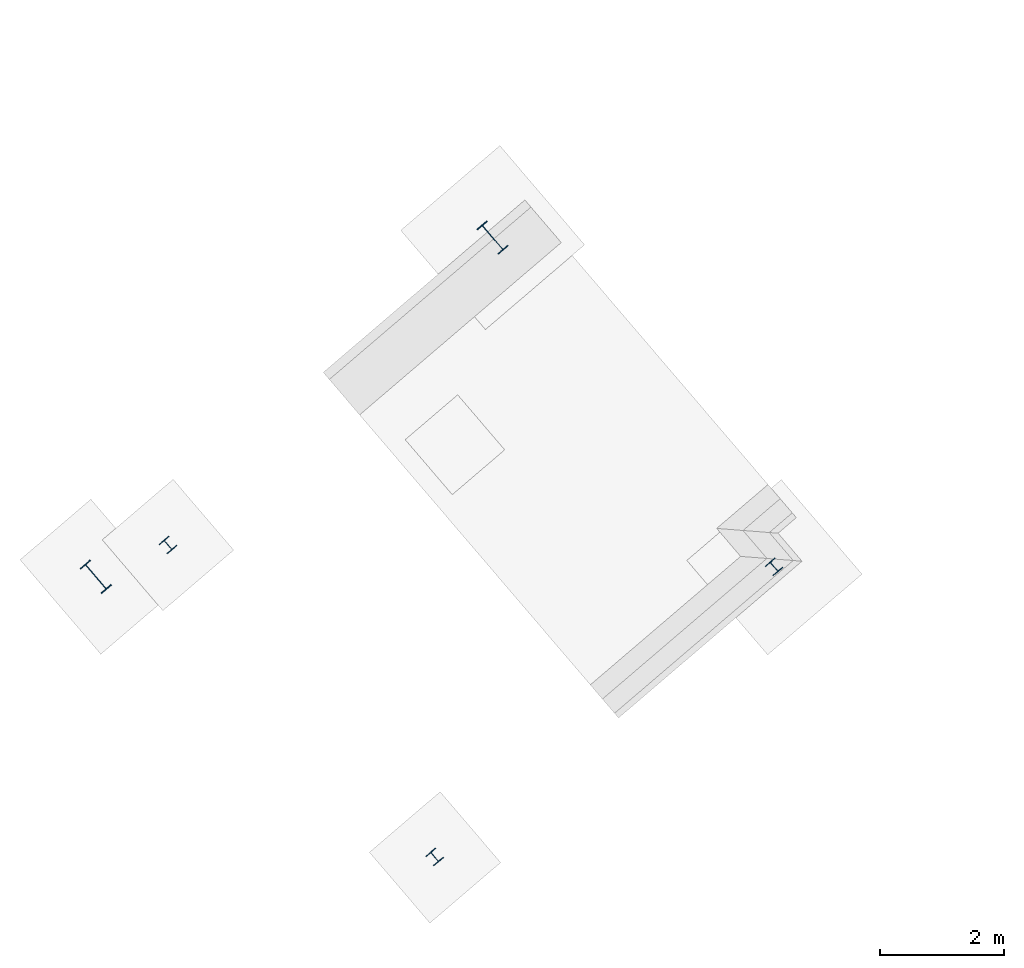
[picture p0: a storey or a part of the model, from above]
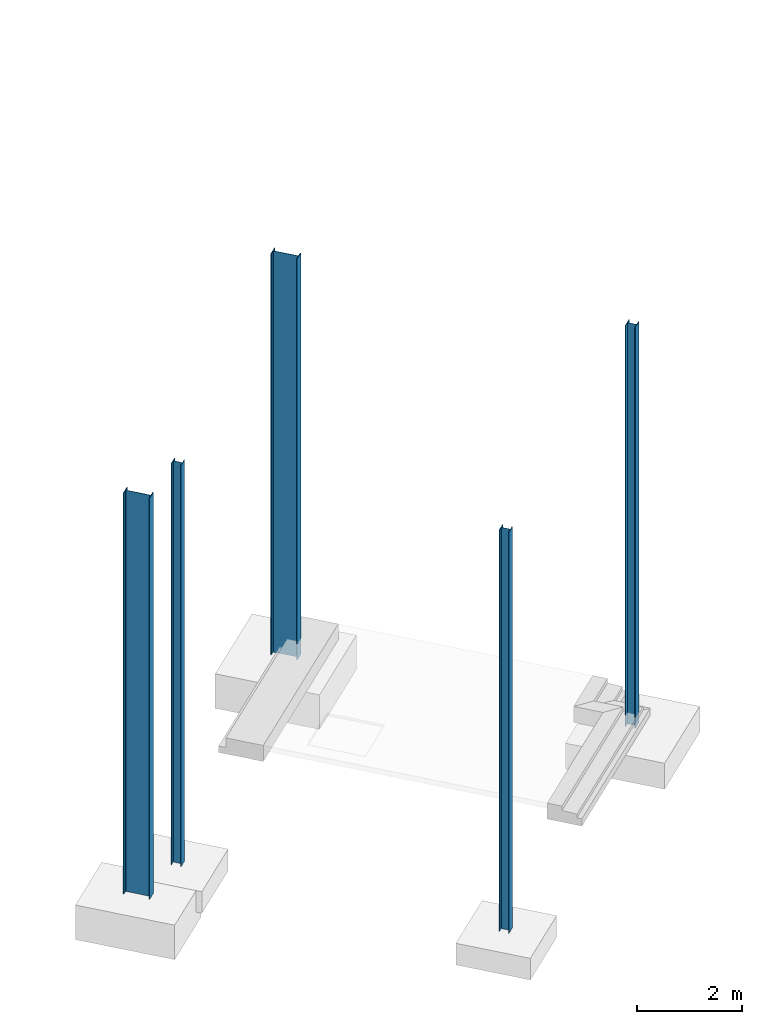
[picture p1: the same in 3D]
Properties of the parts of a building model (IFC2X3)

# File
Description: ViewDefinition [CoordinationView_V2.0]
File name: 12595320
Time: 2024-07-09T11:09:52
Organization: GHD
Written by: ODA IFC SDK 22.8
Made in: 22.1.30.34 - Exporter 22.1.30.34 - Alternate UI 22.1.30.34

# IfcProject, 12595320
LongName: REPOSITORY EXTENSION

# IfcSite, Default
RefLatitude: -33, -52, -58, -799999; RefLongitude: 151, 12, 57, 599999; RefElevation: 0 mm
Pset_ProductRequirements - Category: Project Information

# IfcBuilding
Pset_BuildingCommon - NumberOfStoreys: 4
Pset_ProductRequirements - Category: Project Information

# IfcBuildingStorey: Level:Name and Level (3)
Pset_ProductRequirements - Category: Levels
Name | LongName = Pset_AirSideSystemInformation, Name = Pset_ProductRequirements, Name | Elevation (mm)
Datum | Datum | 0
TOP OF PLANT ROOM | TOP OF PLANT ROOM | 8925
TOP OF CEILING | TOP OF CEILING | 9200

# IfcBeam: ADSK_AUS_Light Gauge-Joists:C20015 (52)
In: Datum
Type - Pset_BeamCommon - IsExternal: no; LoadBearing: yes
Type - Pset_ProductRequirements - Category: Structural Framing
Classification: B10 (Uniformat); Material: Metal - Light Gauge
Pset_BeamCommon - Slope: 0 deg; Reference: C20015
Pset_QuantityTakeOff - Reference: C20015; sets with these values: 2
Name (ADSK_AUS_Light Gauge-Joists:C20015:...) | Span (mm)
644386 | 7047
644389 | 7047
644392 | 7047
644395 | 7047
644398 | 7047
644401 | 7047
644404 | 7047
644407 | 7047
644410 | 7047
644413 | 7047
644416 | 7047
644419 | 7047
644422 | 7047
645018 | 6842
645021 | 6842
645024 | 6842
645027 | 6842
645030 | 6842
645033 | 6842
645036 | 6842
645039 | 6842
645042 | 6842
645045 | 6842
645048 | 6842
645051 | 6842
645054 | 6842
645382 | 4227
645385 | 7148
645388 | 7148
645391 | 7148
645394 | 7148
645397 | 7148
645400 | 7148
645403 | 7148
645406 | 7148
645409 | 7148
645412 | 7148
645415 | 7148
645418 | 7148
645987 | 6932
645990 | 6932
645993 | 6932
645996 | 6932
645999 | 6932
646002 | 6932
646005 | 6932
646008 | 6932
646011 | 6932
646014 | 6932
646017 | 6932
646020 | 6932
646023 | 6932

# IfcBeam: ADSK_AUS_Light Gauge-Joists:C20019 (18)
In: Datum
Type - Pset_BeamCommon - IsExternal: no; LoadBearing: yes
Type - Pset_ProductRequirements - Category: Structural Framing
Classification: B10 (Uniformat); Material: Metal - Light Gauge
Pset_BeamCommon - Slope: 0 deg; Reference: C20019
Pset_QuantityTakeOff - Reference: C20019; sets with these values: 2
Name (ADSK_AUS_Light Gauge-Joists:C20019:...) | Span (mm)
853535 | 5010
853538 | 5010
853541 | 5010
853544 | 5010
853547 | 5010
854987 | 2960
854990 | 2960
854993 | 2960
854996 | 2960
854999 | 2960
855749 | 3110
855751 | 3100
855753 | 580
855755 | 620
855757 | 610
856089 | 300
856175 | 325
856231 | 280

# IfcBeam: ADSK_AU_CHS-Circular Hollow Sections (AS 1163_C350):168.3x4.8CHS EXISTING, ADSK_AU_CHS-Circular Hollow Sections (AS 1163_C350):168.3x4.8CHS EXISTING:496924
In: TOP OF PLANT ROOM
Type - Pset_BeamCommon - IsExternal: no; LoadBearing: yes
Type - Pset_ProductRequirements - Category: Structural Framing
Material: <Unnamed>
Pset_BeamCommon - Slope: 0 deg; Reference: 168.3x4.8CHS EXISTING; Span: 29000 mm
Pset_QuantityTakeOff - Reference: 168.3x4.8CHS EXISTING; sets with these values: 2

# IfcBeam: ADSK_AU_CHS-Circular Hollow Sections (AS 1163_C350):168.3x6.4CHS (29)
Type - Pset_BeamCommon - IsExternal: no; LoadBearing: yes
Type - Pset_ProductRequirements - Category: Structural Framing
Type - Pset_ReinforcementBarPitchOfBeam - Description: STEEL FRAMING
Material: Metal - Steel - 300 MPa
Pset_BeamCommon - Reference: 168.3x6.4CHS
Pset_QuantityTakeOff - Reference: 168.3x6.4CHS
Pset_ReinforcementBarPitchOfBeam - Reference: 168.3x6.4CHS
Name (ADSK_AU_CHS-Circular Hollow Sections (AS 1163_C350):168.3x6.4CHS:...) | In | Span (mm) | Slope (deg)
447945 | TOP OF CEILING | 8400 | 0
448071 | TOP OF CEILING | 6360 | 0
450057 | TOP OF CEILING | 8400 | 0
450227 | TOP OF CEILING | 8400 | 0
450260 | TOP OF CEILING | 8400 | 0
451164 | TOP OF CEILING | 6420.5 | 0
452431 | TOP OF CEILING | 6360 | 0
453757 | TOP OF CEILING | 6760 | 0
456061 | TOP OF CEILING | 6480 | 0
456197 | TOP OF CEILING | 7460 | 0
456199 | TOP OF CEILING | 7467.4 | 0.000102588
456201 | TOP OF CEILING | 7460 | 0
457916 | TOP OF CEILING | 7767.7 | 0
458354 | TOP OF CEILING | 7760 | 0
461023 | TOP OF PLANT ROOM | 8100 | 0
466874 | TOP OF CEILING | 4400 | 0
486064 | TOP OF PLANT ROOM | 8400 | 0
505094 | TOP OF CEILING | 8400 | 0
505642 | TOP OF CEILING | 8400 | 0
506793 | TOP OF CEILING | 8400.1 | 0.287305
506808 | TOP OF CEILING | 8400 | 0
507253 | TOP OF CEILING | 6440 | 0
507673 | TOP OF CEILING | 7020 | 0
510809 | TOP OF PLANT ROOM | 6640 | 0
511162 | TOP OF PLANT ROOM | 6080 | 0
612038 | TOP OF PLANT ROOM | 6980 | 0
612040 | TOP OF PLANT ROOM | 7354.6 | 0
1066787 | TOP OF CEILING | 8275 | 0.000092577
1067047 | TOP OF CEILING | 8275 | 0.000092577

# IfcBeam: ADSK_AU_EA-Equal Angles (AS 3679_1):50x50x5EA (24)
In: TOP OF CEILING
Type - Pset_BeamCommon - IsExternal: no; LoadBearing: yes
Type - Pset_ProductRequirements - Category: Structural Framing
Type - Pset_ReinforcementBarPitchOfBeam - Description: STEEL FRAMING
Pset_BeamCommon - Reference: 50x50x5EA; Span: 660 mm; Slope: 37 deg
Pset_QuantityTakeOff - Reference: 50x50x5EA
Pset_ReinforcementBarPitchOfBeam - Reference: 50x50x5EA
Name (ADSK_AU_EA-Equal Angles (AS 3679_1):50x50x5EA:...)
516959
518426
518509
518511
518528
518530
518594
519063
519114
519116
519133
519135
519349
519351
519989
519991
520215
520217
520234
520236
520590
520592
520611
520613

# IfcBeam: ADSK_AU_EA-Equal Angles (AS 3679_1):65x65x6EA, ADSK_AU_EA-Equal Angles (AS 3679_1):65x65x6EA:1106605
In: Datum
Type - Pset_BeamCommon - IsExternal: no; LoadBearing: yes
Type - Pset_ProductRequirements - Category: Structural Framing
Type - Pset_ReinforcementBarPitchOfBeam - Description: STEEL FRAMING
Material: Metal - Steel - 300 MPa
Pset_BeamCommon - Slope: 0 deg; Reference: 65x65x6EA; Span: 270 mm
Pset_QuantityTakeOff - Reference: 65x65x6EA
Pset_ReinforcementBarPitchOfBeam - Reference: 65x65x6EA

# IfcBeam: ADSK_AU_EA-Equal Angles (AS 3679_1):90x90x10EA (26)
Type - Pset_BeamCommon - IsExternal: no; LoadBearing: yes
Type - Pset_ProductRequirements - Category: Structural Framing
Type - Pset_ReinforcementBarPitchOfBeam - Description: STEEL FRAMING
Material: Metal - Steel - 300 MPa
Pset_BeamCommon - Reference: 90x90x10EA
Pset_QuantityTakeOff - Reference: 90x90x10EA
Pset_ReinforcementBarPitchOfBeam - Reference: 90x90x10EA
Name (ADSK_AU_EA-Equal Angles (AS 3679_1):90x90x10EA:...) | In | Span (mm) | Slope (deg)
461464 | TOP OF PLANT ROOM | 10040.4 | 33.2153
461687 | TOP OF PLANT ROOM | 10040.4 | 33.2153
486003 | TOP OF PLANT ROOM | 10375 | 39.6164
486009 | TOP OF PLANT ROOM | 10100 | 36.7247
486487 | TOP OF PLANT ROOM | 10350 | 39.6335
486578 | TOP OF PLANT ROOM | 10060 | 36.708
507776 | TOP OF PLANT ROOM | 8880 | 38.3458
508056 | TOP OF PLANT ROOM | 8860 | 40.7268
508541 | TOP OF PLANT ROOM | 9480 | 42.2043
508543 | TOP OF PLANT ROOM | 9100 | 39.9247
611443 | TOP OF PLANT ROOM | 8460 | 38.695
611445 | TOP OF PLANT ROOM | 8860 | 41.9713
611447 | TOP OF PLANT ROOM | 9020 | 41.1549
611449 | TOP OF PLANT ROOM | 9420 | 43.3491
611451 | Datum | 8660 | 38.849
611453 | Datum | 8860 | 38.8348
611455 | Datum | 8900 | 38.0443
611457 | Datum | 8965 | 38.0468
671669 | Datum | 200 | 0
768591 | Datum | 8740 | 38.9314
768593 | Datum | 9020 | 39.7876
768827 | Datum | 8800 | 38.727
768829 | Datum | 8840 | 38.775
871857 | TOP OF PLANT ROOM | 10040.4 | 33.9341
871859 | TOP OF PLANT ROOM | 10040.5 | 33.2149
1080870 | Datum | 255 | 0

# IfcBeam: ADSK_AU_Light Gauge-Zeds:Z20012 (35)
Type - Pset_BeamCommon - IsExternal: no; LoadBearing: yes
Type - Pset_ProductRequirements - Category: Structural Framing
Classification: B10 (Uniformat); Material: Metal - Steel - 345 MPa
Pset_BeamCommon - Reference: Z20012
Pset_QuantityTakeOff - Reference: Z20012; sets with these values: 2
Name (ADSK_AU_Light Gauge-Zeds:Z20012:...) | In | Span (mm) | Slope (deg)
585773 | TOP OF CEILING | 29400 | 3.78054
585860 | TOP OF CEILING | 29400 | 3.78054
647515 | Datum | 8999 | 0
647518 | Datum | 8999 | 0
647521 | Datum | 8999 | 0
647524 | Datum | 8999 | 0
647527 | Datum | 8999 | 0
647530 | Datum | 8999 | 0
647533 | Datum | 8999 | 0
647536 | Datum | 8999 | 0
647539 | Datum | 8999 | 0
647542 | Datum | 8999 | 0
647545 | Datum | 8999 | 0
648481 | Datum | 8999 | 0
648483 | Datum | 8999 | 0
648485 | Datum | 8999 | 0
648487 | Datum | 8999 | 0
648489 | Datum | 8999 | 0
648491 | Datum | 8999 | 0
648493 | Datum | 8999 | 0
648495 | Datum | 8999 | 0
648497 | Datum | 8999 | 0
648499 | Datum | 8999 | 0
648501 | Datum | 8999 | 0
764615 | Datum | 8199 | 0
764617 | Datum | 8240 | 0
764619 | Datum | 8199 | 0
764621 | Datum | 8199 | 0
764623 | Datum | 8199 | 0
764625 | Datum | 8199 | 0
764627 | Datum | 8199 | 0
764629 | Datum | 8199 | 0
764631 | Datum | 8199 | 0
764633 | Datum | 8199 | 0
764635 | Datum | 8235 | 0

# IfcBeam: ADSK_AU_Light Gauge-Zeds:Z20015 (57)
Type - Pset_BeamCommon - IsExternal: no; LoadBearing: yes
Type - Pset_ProductRequirements - Category: Structural Framing
Classification: B10 (Uniformat)
Pset_BeamCommon - Slope: 0 deg; Reference: Z20015
Pset_QuantityTakeOff - Reference: Z20015; sets with these values: 2
Name (ADSK_AU_Light Gauge-Zeds:Z20015:...) | In | Material | Span (mm)
646382 | Datum | Metal - Steel - 345 MPa | 5284
646385 | Datum | Metal - Steel - 345 MPa | 5284
646388 | Datum | Metal - Steel - 345 MPa | 5284
649198 | Datum | Metal - Steel - 345 MPa | 7040
649200 | Datum | Metal - Steel - 345 MPa | 7040
649202 | Datum | Metal - Steel - 345 MPa | 7040
649204 | Datum | Metal - Steel - 345 MPa | 7040
649206 | Datum | Metal - Steel - 345 MPa | 7040
649208 | Datum | Metal - Steel - 345 MPa | 7040
649210 | Datum | Metal - Steel - 345 MPa | 7040
649212 | Datum | Metal - Steel - 345 MPa | 7040
649214 | Datum | Metal - Steel - 345 MPa | 7040
653207 | TOP OF CEILING | Metal - Steel - 345 MPa | 8164
653209 | TOP OF CEILING | Metal - Steel - 345 MPa | 8164
653211 | TOP OF CEILING | Metal - Steel - 345 MPa | 8164
653213 | TOP OF CEILING | Metal - Steel - 345 MPa | 8164
653215 | TOP OF CEILING | Metal - Steel - 345 MPa | 8164
653218 | TOP OF CEILING | Metal - Steel - 345 MPa | 8164
653220 | TOP OF CEILING | Metal - Steel - 345 MPa | 8164
653222 | TOP OF CEILING | Metal - Light Gauge | 8164
653224 | TOP OF CEILING | Metal - Steel - 345 MPa | 8164
653226 | TOP OF CEILING | Metal - Steel - 345 MPa | 8164
653228 | TOP OF CEILING | Metal - Steel - 345 MPa | 8164
653230 | TOP OF CEILING | Metal - Steel - 345 MPa | 8164
653232 | TOP OF CEILING | Metal - Steel - 345 MPa | 8164
653439 | TOP OF CEILING | Metal - Steel - 345 MPa | 8164
653441 | TOP OF CEILING | Metal - Steel - 345 MPa | 8164
653972 | TOP OF CEILING | Metal - Steel - 345 MPa | 9000
653974 | TOP OF CEILING | Metal - Steel - 345 MPa | 9000
653976 | TOP OF CEILING | Metal - Steel - 345 MPa | 9000
653978 | TOP OF CEILING | Metal - Steel - 345 MPa | 9000
653980 | TOP OF CEILING | Metal - Steel - 345 MPa | 9000
653983 | TOP OF CEILING | Metal - Steel - 345 MPa | 9000
653985 | TOP OF CEILING | Metal - Steel - 345 MPa | 9000
653987 | TOP OF CEILING | Metal - Steel - 345 MPa | 9000
653989 | TOP OF CEILING | Metal - Steel - 345 MPa | 9000
653991 | TOP OF CEILING | Metal - Steel - 345 MPa | 9000
653993 | TOP OF CEILING | Metal - Steel - 345 MPa | 9000
653995 | TOP OF CEILING | Metal - Steel - 345 MPa | 9000
653997 | TOP OF CEILING | Metal - Steel - 345 MPa | 9000
654001 | TOP OF CEILING | Metal - Steel - 345 MPa | 9000
654003 | TOP OF CEILING | Metal - Steel - 345 MPa | 9000
654415 | TOP OF CEILING | Metal - Steel - 345 MPa | 9000
654417 | TOP OF CEILING | Metal - Steel - 345 MPa | 9000
654419 | TOP OF CEILING | Metal - Steel - 345 MPa | 9000
654421 | TOP OF CEILING | Metal - Steel - 345 MPa | 9000
654423 | TOP OF CEILING | Metal - Steel - 345 MPa | 9000
654425 | TOP OF CEILING | Metal - Steel - 345 MPa | 9000
654427 | TOP OF CEILING | Metal - Steel - 345 MPa | 9000
654429 | TOP OF CEILING | Metal - Steel - 345 MPa | 9000
654431 | TOP OF CEILING | Metal - Steel - 345 MPa | 9000
654433 | TOP OF CEILING | Metal - Steel - 345 MPa | 9000
654435 | TOP OF CEILING | Metal - Steel - 345 MPa | 9000
654437 | TOP OF CEILING | Metal - Steel - 345 MPa | 9000
654439 | TOP OF CEILING | Metal - Steel - 345 MPa | 9000
654442 | TOP OF CEILING | Metal - Steel - 345 MPa | 9000
654444 | TOP OF CEILING | Metal - Steel - 345 MPa | 9000

# IfcBeam: ADSK_AU_Light Gauge-Zeds:Z20019 (15)
In: TOP OF CEILING
Type - Pset_BeamCommon - IsExternal: no; LoadBearing: yes
Type - Pset_ProductRequirements - Category: Structural Framing
Classification: B10 (Uniformat); Material: Metal - Light Gauge
Pset_BeamCommon - Slope: 0 deg; Reference: Z20019; Span: 7035 mm
Pset_QuantityTakeOff - Reference: Z20019; sets with these values: 2
Name (ADSK_AU_Light Gauge-Zeds:Z20019:...)
652011
652013
652015
652017
652019
652089
652091
652093
652095
652097
652099
652101
652103
652187
652189

# IfcBeam: ADSK_AU_Light Gauge-Zeds:Z20024 (40)
In: TOP OF CEILING
Type - Pset_BeamCommon - IsExternal: no; LoadBearing: yes
Type - Pset_ProductRequirements - Category: Structural Framing
Classification: B10 (Uniformat); Material: Metal - Light Gauge
Pset_BeamCommon - Slope: 0 deg; Reference: Z20024
Pset_QuantityTakeOff - Reference: Z20024; sets with these values: 2
Name (ADSK_AU_Light Gauge-Zeds:Z20024:...) | Span (mm)
646866 | 7035
646869 | 7035
646872 | 7035
646875 | 7035
646878 | 7035
652279 | 7035
652281 | 7035
652283 | 7035
652514 | 7035
652516 | 7035
652610 | 9000
652612 | 9000
652614 | 9000
652619 | 9000
652621 | 9000
652815 | 9000
652817 | 9000
652819 | 9000
652822 | 9000
652824 | 9000
653025 | 8192
653027 | 8192
653029 | 8192
653032 | 8192
653034 | 8192
653579 | 8161
653581 | 8161
653583 | 8161
653585 | 8161
653587 | 8161
653791 | 9000
653793 | 9000
653795 | 9000
653797 | 9000
653799 | 9000
654252 | 9000
654254 | 9000
654256 | 9000
654258 | 9000
654260 | 9000

# IfcBeam: ADSK_AU_PFC-Parallel Flange Channels (AS 3679_1):200PFC (8)
Type - Pset_BeamCommon - IsExternal: no; LoadBearing: yes
Type - Pset_ProductRequirements - Category: Structural Framing
Type - Pset_ReinforcementBarPitchOfBeam - Description: STEEL FRAMING
Material: Metal - Steel - 300 MPa
Pset_BeamCommon - Slope: 0 deg; Reference: 200PFC
Pset_QuantityTakeOff - Reference: 200PFC
Pset_ReinforcementBarPitchOfBeam - Reference: 200PFC
Name (ADSK_AU_PFC-Parallel Flange Channels (AS 3679_1):200PFC:...) | In | Span (mm)
476301 | TOP OF CEILING | 4560
494982 | TOP OF PLANT ROOM | 4240
495150 | TOP OF PLANT ROOM | 4240
495163 | TOP OF PLANT ROOM | 4240
495176 | TOP OF PLANT ROOM | 4240
495189 | TOP OF CEILING | 4240
495233 | TOP OF CEILING | 4240
495246 | TOP OF CEILING | 4240

# IfcBeam: ADSK_AU_PFC-Parallel Flange Channels (AS 3679_1):250PFC (3)
In: Datum
Type - Pset_BeamCommon - IsExternal: no; LoadBearing: yes
Type - Pset_ProductRequirements - Category: Structural Framing
Type - Pset_ReinforcementBarPitchOfBeam - Description: STEEL FRAMING
Material: Metal - Light Gauge Painted
Pset_BeamCommon - Reference: 250PFC
Pset_QuantityTakeOff - Reference: 250PFC
Pset_ReinforcementBarPitchOfBeam - Reference: 250PFC
Name (ADSK_AU_PFC-Parallel Flange Channels (AS 3679_1):250PFC:...) | Span (mm) | Slope (deg)
544530 | 3084 | 5.00001
545588 | 3222.7 | 5.00006
546929 | 5200 | 0

# IfcBeam: ADSK_AU_PFC-Parallel Flange Channels (AS 3679_1):300PFC, ADSK_AU_PFC-Parallel Flange Channels (AS 3679_1):300PFC:543160
In: Datum
Type - Pset_BeamCommon - IsExternal: no; LoadBearing: yes
Type - Pset_ProductRequirements - Category: Structural Framing
Type - Pset_ReinforcementBarPitchOfBeam - Description: STEEL FRAMING
Material: Metal - Light Gauge Painted
Pset_BeamCommon - Slope: 0 deg; Reference: 300PFC; Span: 7860 mm
Pset_QuantityTakeOff - Reference: 300PFC
Pset_ReinforcementBarPitchOfBeam - Reference: 300PFC

# IfcBeam: ADSK_AU_RHS-Rectangular Hollow Sections (AS 1163_C350):150x100x5.0RHS (3)
In: Datum
Type - Pset_BeamCommon - IsExternal: no; LoadBearing: yes
Type - Pset_ProductRequirements - Category: Structural Framing
Type - Pset_ReinforcementBarPitchOfBeam - Description: STEEL FRAMING
Pset_BeamCommon - Slope: 0 deg; Reference: 150x100x5.0RHS
Pset_QuantityTakeOff - Reference: 150x100x5.0RHS
Pset_ReinforcementBarPitchOfBeam - Reference: 150x100x5.0RHS
Name (ADSK_AU_RHS-Rectangular Hollow Sections (AS 1163_C350):150x100x5.0RHS:...) | Material | Span (mm)
540188 | Metal - Light Gauge Painted | 3060
570080 | Metal - Steel - 300 MPa | 6840
589344 | Metal - Steel - 300 MPa | 6745

# IfcBeam: ADSK_AU_Round Bars (AS 3679_1):20ROD (2)
In: Datum
Type - Pset_BeamCommon - IsExternal: no; LoadBearing: yes
Type - Pset_ProductRequirements - Category: Structural Framing
Type - Pset_ReinforcementBarPitchOfBeam - Description: STEEL FRAMING
Material: Metal - Light Gauge
Pset_BeamCommon - Reference: 20ROD
Pset_QuantityTakeOff - Reference: 20ROD
Pset_ReinforcementBarPitchOfBeam - Reference: 20ROD
Name (ADSK_AU_Round Bars (AS 3679_1):20ROD:...) | Span (mm) | Slope (deg)
547200 | 5820 | 2.46192
547300 | 5900 | 2.42851

# IfcBeam: ADSK_AU_Round Bars (AS 3679_1):24ROD (25)
In: TOP OF CEILING
Type - Pset_BeamCommon - IsExternal: no; LoadBearing: yes
Type - Pset_ProductRequirements - Category: Structural Framing
Pset_BeamCommon - Reference: 24ROD
Pset_QuantityTakeOff - Reference: 24ROD; sets with these values: 2
Name (ADSK_AU_Round Bars (AS 3679_1):24ROD:...) | Span (mm) | Slope (deg)
448184 | 9600 | 2.08937
448467 | 9732.1 | 4.3242
450519 | 9593.1 | 1.59011
450521 | 9600 | 3.28437
451956 | 9560 | 2.09812
451958 | 9660 | 2.96695
453718 | 9920 | 3.46759
453720 | 9700 | 2.65901
454938 | 10098.7 | 2.72434
454940 | 10280 | 2.78786
454942 | 10400 | 2.75567
454944 | 10380 | 3.31457
454946 | 10380 | 4.36488
454948 | 10210 | 2.91936
454950 | 10874.1 | 3.09905
454952 | 10860.2 | 1.10798
505726 | 11106.2 | 2.32214
505750 | 11100.3 | 1.3741
505855 | 10940 | 4.19356
505870 | 7251.6 | 0
505893 | 11099.2 | 1.11613
506960 | 11321.1 | 1.06287
507005 | 11321.1 | 1.06287 | Material: Colorbond Paint - Basalt
507054 | 11321.1 | 1.06287
507099 | 11321.1 | 1.06287

# IfcBeam: ADSK_AU_Round Bars (AS 3679_1):24ROD (EXISTING) (4)
Type - Pset_BeamCommon - IsExternal: no; LoadBearing: yes
Type - Pset_ProductRequirements - Category: Structural Framing
Pset_BeamCommon - Reference: 24ROD (EXISTING)
Pset_QuantityTakeOff - Reference: 24ROD (EXISTING); sets with these values: 2
Name (ADSK_AU_Round Bars (AS 3679_1):24ROD (EXISTING):...) | In | Span (mm) | Slope (deg)
497516 | TOP OF PLANT ROOM | 7400 | 39.3869
498346 | Datum | 7330 | 41.429
498640 | TOP OF PLANT ROOM | 9520 | 35.1426
498642 | Datum | 9080 | 32.1768

# IfcBeam: ADSK_AU_SHS-Square Hollow Sections (AS 1163_C350):150x150x6.0SHS (2)
In: Datum
Type - Pset_BeamCommon - IsExternal: no; LoadBearing: yes
Type - Pset_ProductRequirements - Category: Structural Framing
Type - Pset_ReinforcementBarPitchOfBeam - Description: STEEL FRAMING
Material: Metal - Steel - 300 MPa
Pset_BeamCommon - Slope: 0 deg; Reference: 150x150x6.0SHS
Pset_QuantityTakeOff - Reference: 150x150x6.0SHS
Pset_ReinforcementBarPitchOfBeam - Reference: 150x150x6.0SHS
Name (ADSK_AU_SHS-Square Hollow Sections (AS 1163_C350):150x150x6.0SHS:...) | Span (mm)
547857 | 7200
549237 | 7160

# IfcBeam: ADSK_AU_UB-Universal Beams (AS 3679_1):200UB18.2 (2)
In: TOP OF CEILING
Type - Pset_BeamCommon - IsExternal: no; LoadBearing: yes
Type - Pset_ProductRequirements - Category: Structural Framing
Type - Pset_ReinforcementBarPitchOfBeam - Description: STEEL FRAMING
Pset_BeamCommon - Reference: 200UB18.2
Pset_QuantityTakeOff - Reference: 200UB18.2
Pset_ReinforcementBarPitchOfBeam - Reference: 200UB18.2
Name (ADSK_AU_UB-Universal Beams (AS 3679_1):200UB18.2:...) | Span (mm) | Slope (deg)
469927 | 7163.5 | 84.3745
494460 | 6500 | 90

# IfcBeam: ADSK_AU_UB-Universal Beams (AS 3679_1):310UB40.4, ADSK_AU_UB-Universal Beams (AS 3679_1):310UB40.4:466103
In: TOP OF CEILING
Type - Pset_BeamCommon - IsExternal: no; LoadBearing: yes
Type - Pset_ProductRequirements - Category: Structural Framing
Type - Pset_ReinforcementBarPitchOfBeam - Description: STEEL FRAMING
Pset_BeamCommon - Reference: 310UB40.4; Span: 29660 mm; Slope: 3.98485 deg
Pset_QuantityTakeOff - Reference: 310UB40.4
Pset_ReinforcementBarPitchOfBeam - Reference: 310UB40.4

# IfcBeam: ADSK_UK_Light Gauge-Zeds-Purlin:Metsec-202Z14 (60)
Type - Pset_BeamCommon - IsExternal: no; LoadBearing: yes
Type - Pset_ProductRequirements - Category: Structural Framing
Classification: B10 (Uniformat); Material: Metal - Steel - 300 MPa
Pset_BeamCommon - Reference: Metsec-202Z14
Pset_QuantityTakeOff - Reference: Metsec-202Z14; sets with these values: 2
Name (ADSK_UK_Light Gauge-Zeds-Purlin:Metsec-202Z14:...) | In | Slope (deg) | Span (mm)
468644 | TOP OF PLANT ROOM | 0 | 4900
468943 | TOP OF PLANT ROOM | 0 | 4900
468957 | Datum | 0 | 4900
468971 | Datum | 0 | 4900
468985 | Datum | 0 | 4900
468999 | Datum | 0 | 4900
469013 | Datum | 0 | 4900
469087 | TOP OF PLANT ROOM | 0 | 29000
469690 | TOP OF PLANT ROOM | 0 | 29000
469703 | Datum | 0 | 29000
469718 | Datum | 0 | 24580
469733 | Datum | 0 | 2240
469748 | Datum | 0 | 2240
469763 | Datum | 0 | 2260
470765 | TOP OF CEILING | 0 | 6000
475768 | TOP OF CEILING | 0 | 1587
475872 | TOP OF CEILING | 0 | 6000
475885 | TOP OF CEILING | 0 | 5900
475899 | TOP OF CEILING | 0.00000625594 | 5951
475956 | TOP OF CEILING | 0 | 6000
476011 | TOP OF CEILING | 0 | 6000
476074 | TOP OF CEILING | 0 | 6000
476129 | TOP OF CEILING | 0 | 6000
476241 | TOP OF CEILING | 0 | 6000
476384 | TOP OF CEILING | 0 | 6000
493490 | TOP OF PLANT ROOM | 0 | 4240
494144 | TOP OF PLANT ROOM | 0 | 4240
494157 | TOP OF PLANT ROOM | 0 | 4240
494170 | TOP OF PLANT ROOM | 0 | 4240
494210 | TOP OF CEILING | 0 | 4240
494223 | TOP OF CEILING | 0 | 4240
494236 | TOP OF CEILING | 0 | 4240
494249 | TOP OF CEILING | 0 | 4240
494286 | TOP OF CEILING | 0 | 4240
496260 | TOP OF PLANT ROOM | 0.0182882 | 4640
496262 | TOP OF PLANT ROOM | 0.0454991 | 4640
496264 | Datum | 0 | 4680
496266 | Datum | 0 | 4900
496268 | Datum | 0 | 4900
496270 | Datum | 0 | 4660
496272 | Datum | 0 | 4680
499293 | TOP OF PLANT ROOM | 0 | 29000
499506 | TOP OF PLANT ROOM | 0 | 4660
499520 | TOP OF PLANT ROOM | 0 | 4680
499534 | TOP OF PLANT ROOM | 0 | 4520
499548 | TOP OF CEILING | 0 | 4695
500190 | TOP OF PLANT ROOM | 0 | 29000
500207 | TOP OF PLANT ROOM | 0 | 29000
500224 | TOP OF CEILING | 0 | 29000
500241 | TOP OF CEILING | 0 | 19300
500256 | TOP OF CEILING | 0 | 6920
501930 | TOP OF PLANT ROOM | 0 | 4900
502167 | TOP OF PLANT ROOM | 0 | 4900
513728 | Datum | 0 | 2220
513762 | Datum | 0 | 2220
513806 | Datum | 0 | 2220
666759 | Datum | 0 | 2220
668257 | Datum | 0 | 20200
668333 | Datum | 0 | 20160
668767 | Datum | 0 | 20160

# IfcBuildingElementProxy: Fascia Purlin:Fascia Purlin, Fascia Purlin:Fascia Purlin:1133160
In: TOP OF CEILING
Type - Material: <Unnamed>
Type - Pset_ProductRequirements - Category: Structural Framing
Pset_BuildingElementProxyCommon - Reference: Fascia Purlin; sets with these values: 2
Pset_ProvisionForVoid - Depth: 31400 mm

# IfcBuildingElementProxy: Slab Edge:Thickening Edge (3)
In: Datum
Type - Pset_ProductRequirements - Category: Floors: Slab Edges
Pset_BuildingElementProxyCommon - Reference: Thickening Edge; sets with these values: 2
Name (Slab Edge:Thickening Edge:...)
1080158
1083220
1083226

# IfcBuildingElementProxy: Slab Edge:Thickening Edge 2, Slab Edge:Thickening Edge 2:1086235
In: Datum
Type - Pset_ProductRequirements - Category: Floors: Slab Edges
Pset_BuildingElementProxyCommon - Reference: Thickening Edge 2; sets with these values: 2
Pset_ProvisionForVoid - Shape: Undefined; Depth: 4268.39 mm

# IfcColumn: ADSK_AU_SHS-Square Hollow Sections-Column (AS 1163_C350):100x100x5.0SHS (8)
In: Datum
Type - PredefinedType: COLUMN; Material: Metal - Steel - 300 MPa
Type - Pset_ColumnCommon - IsExternal: no; LoadBearing: yes
Type - Pset_ProductRequirements - Category: Structural Columns
Type - Pset_ReinforcementBarPitchOfColumn - Description: STEEL COLUMN
Pset_ColumnCommon - Reference: 100x100x5.0SHS
Pset_QuantityTakeOff - Reference: 100x100x5.0SHS
Pset_ReinforcementBarPitchOfColumn - Reference: 100x100x5.0SHS
Name (ADSK_AU_SHS-Square Hollow Sections-Column (AS 1163_C350):100x100x5.0SHS:...)
538913
539372
548377
549239
569776
589556
666456
667581

# IfcColumn: ADSK_AU_SHS-Square Hollow Sections-Column (AS 1163_C350):150x150x5.0SHS (3)
In: Datum
Type - PredefinedType: COLUMN; Material: Metal - Steel - 300 MPa
Type - Pset_ColumnCommon - IsExternal: no; LoadBearing: yes
Type - Pset_ProductRequirements - Category: Structural Columns
Type - Pset_ReinforcementBarPitchOfColumn - Description: STEEL COLUMN
Pset_ColumnCommon - Reference: 150x150x5.0SHS
Pset_QuantityTakeOff - Reference: 150x150x5.0SHS
Pset_ReinforcementBarPitchOfColumn - Reference: 150x150x5.0SHS
Name (ADSK_AU_SHS-Square Hollow Sections-Column (AS 1163_C350):150x150x5.0SHS:...)
539430
539738
539761

# IfcColumn: ADSK_AU_UB-Universal Beams-Column (AS 3679_1):360UB44.7 (EXISTING) (3)
In: Datum
Type - PredefinedType: COLUMN; Material: Metal - Steel - 300 MPa
Type - Pset_ColumnCommon - IsExternal: no; LoadBearing: yes
Type - Pset_ProductRequirements - Category: Structural Columns
Pset_ColumnCommon - Reference: 360UB44.7 (EXISTING)
Pset_QuantityTakeOff - Reference: 360UB44.7 (EXISTING); sets with these values: 2
Name (ADSK_AU_UB-Universal Beams-Column (AS 3679_1):360UB44.7 (EXISTING):...)
445959
445974
445991

# IfcColumn: ADSK_AU_UB-Universal Beams-Column (AS 3679_1):460UB67.1 (2)
In: Datum
Type - PredefinedType: COLUMN; Material: Metal - Steel - 300 MPa
Type - Pset_ColumnCommon - IsExternal: no; LoadBearing: yes
Type - Pset_ProductRequirements - Category: Structural Columns
Type - Pset_ReinforcementBarPitchOfColumn - Description: STEEL COLUMN
Description: BP{9986EAF8-8209-4BFB-B9E4-6B7E1651E2E1}
Pset_ColumnCommon - Reference: 460UB67.1
Pset_QuantityTakeOff - Reference: 460UB67.1
Pset_ReinforcementBarPitchOfColumn - Reference: 460UB67.1
ProfileProperties - SectionFamily: {3C230476-3704-4959-9E77-0935CE245F3A}BP; Section: BP{9986EAF8-8209-4BFB-B9E4-6B7E1651E2E1}
Name (ADSK_AU_UB-Universal Beams-Column (AS 3679_1):460UB67.1:...)
622792
610739

# IfcColumn: ADSK_AU_UB-Universal Beams-Column (AS 3679_1):530UB92.4 (15)
In: Datum
Type - PredefinedType: COLUMN; Material: Metal - Steel - 300 MPa
Type - Pset_ColumnCommon - IsExternal: no; LoadBearing: yes
Type - Pset_ProductRequirements - Category: Structural Columns
Type - Pset_ReinforcementBarPitchOfColumn - Description: STEEL COLUMN
Pset_ColumnCommon - Reference: 530UB92.4
Pset_QuantityTakeOff - Reference: 530UB92.4
Pset_ReinforcementBarPitchOfColumn - Reference: 530UB92.4
Name (ADSK_AU_UB-Universal Beams-Column (AS 3679_1):530UB92.4:...) | Description = Section | SectionFamily
445778
445924
447251
447313
447328
1073207
1073524
623076 | BP{3C230476-3704-4959-9E77-0935CE245F3A} | {3C230476-3704-4959-9E77-0935CE245F3A}BP
622994 | BP{3C230476-3704-4959-9E77-0935CE245F3A} | {3C230476-3704-4959-9E77-0935CE245F3A}BP
622851 | BP{3C230476-3704-4959-9E77-0935CE245F3A} | {3C230476-3704-4959-9E77-0935CE245F3A}BP
449362 | BP{3C230476-3704-4959-9E77-0935CE245F3A} | {3C230476-3704-4959-9E77-0935CE245F3A}BP
446577 | BP{3C230476-3704-4959-9E77-0935CE245F3A} | {3C230476-3704-4959-9E77-0935CE245F3A}BP
446625 | BP{3C230476-3704-4959-9E77-0935CE245F3A} | {3C230476-3704-4959-9E77-0935CE245F3A}BP
446642 | BP{3C230476-3704-4959-9E77-0935CE245F3A} | {3C230476-3704-4959-9E77-0935CE245F3A}BP
623118 | BP{3C230476-3704-4959-9E77-0935CE245F3A} | {3C230476-3704-4959-9E77-0935CE245F3A}BP

# IfcColumn: ADSK_AU_UC-Universal Columns-Column (AS 3679_1):200UC46.2 (3)
In: Datum
Type - PredefinedType: COLUMN; Material: Metal - Steel - 300 MPa
Type - Pset_ColumnCommon - IsExternal: no; LoadBearing: yes
Type - Pset_ProductRequirements - Category: Structural Columns
Type - Pset_ReinforcementBarPitchOfColumn - Description: STEEL COLUMN
Pset_ColumnCommon - Reference: 200UC46.2
Pset_QuantityTakeOff - Reference: 200UC46.2
Pset_ReinforcementBarPitchOfColumn - Reference: 200UC46.2
Name (ADSK_AU_UC-Universal Columns-Column (AS 3679_1):200UC46.2:...)
1073393
1073455
1073601

# IfcColumn: ADSK_AU_UC-Universal Columns-Column (AS 3679_1):310UC118 (5)
In: Datum
Type - PredefinedType: COLUMN; Material: Metal - Steel - 300 MPa
Type - Pset_ColumnCommon - IsExternal: no; LoadBearing: yes
Type - Pset_ProductRequirements - Category: Structural Columns
Type - Pset_ReinforcementBarPitchOfColumn - Description: STEEL COLUMN
Pset_ColumnCommon - Reference: 310UC118
Pset_QuantityTakeOff - Reference: 310UC118
Pset_ReinforcementBarPitchOfColumn - Reference: 310UC118
Name (ADSK_AU_UC-Universal Columns-Column (AS 3679_1):310UC118:...)
444763
444779
610593
610597
615597

# IfcColumn: ADSK_AU_UC-Universal Columns-Column (AS 3679_1):310UC118, ADSK_AU_UC-Universal Columns-Column (AS 3679_1):310UC118:444334
In: Datum
Type - PredefinedType: COLUMN; Material: Metal - Steel - ASTM A36
Type - Pset_ColumnCommon - IsExternal: no; LoadBearing: yes
Type - Pset_ProductRequirements - Category: Structural Columns
Type - Pset_ReinforcementBarPitchOfColumn - Description: STEEL COLUMN
Pset_ColumnCommon - Reference: 310UC118
Pset_QuantityTakeOff - Reference: 310UC118
Pset_ReinforcementBarPitchOfColumn - Reference: 310UC118

# IfcElementAssembly: Structural Beam System:Structural Beam System 1 (21)
PredefinedType: BEAM_GRID
Pset_ProductRequirements - Category: Structural Beam Systems
Pset_QuantityTakeOff - Reference: Structural Beam System 1
Name (Structural Beam System:Structural Beam System 1:...) | In
644317 | Datum
644973 | Datum
645354 | Datum
645959 | Datum
646284 | Datum
646809 | TOP OF CEILING
647410 | Datum
648475 | Datum
652005 | TOP OF CEILING
652274 | TOP OF CEILING
652605 | TOP OF CEILING
652810 | TOP OF CEILING
653020 | TOP OF CEILING
653202 | TOP OF CEILING
653573 | TOP OF CEILING
653785 | TOP OF CEILING
653967 | TOP OF CEILING
654246 | TOP OF CEILING
654410 | TOP OF CEILING
853458 | Datum
854653 | Datum

# IfcMember: ADSK_AU_Light Gauge-Zeds:Z20012 (22)
Type - PredefinedType: BRACE; Classification: B10 (Uniformat); Material: Metal - Steel - 345 MPa
Type - Pset_MemberCommon - IsExternal: no; LoadBearing: yes
Type - Pset_ProductRequirements - Category: Structural Framing
Pset_MemberCommon - Slope: 0 deg; Reference: Z20012
Pset_QuantityTakeOff - Reference: Z20012
Name (ADSK_AU_Light Gauge-Zeds:Z20012:...) | In | Span (mm)
568773 | TOP OF PLANT ROOM | 9240
568775 | TOP OF PLANT ROOM | 9240
568777 | TOP OF PLANT ROOM | 9240
568779 | TOP OF CEILING | 8700
568781 | TOP OF CEILING | 8500
568852 | Datum | 9240
568893 | Datum | 9240
568907 | Datum | 9240
568921 | Datum | 9240
980656 | Datum | 11100
980658 | Datum | 11100
980660 | Datum | 11100
980662 | Datum | 11200
980668 | TOP OF PLANT ROOM | 9240
980670 | TOP OF CEILING | 9240
980672 | TOP OF CEILING | 9240
980861 | TOP OF PLANT ROOM | 9240
980863 | TOP OF PLANT ROOM | 9240
980865 | TOP OF CEILING | 8700
980867 | TOP OF CEILING | 8500
981292 | TOP OF PLANT ROOM | 9240
981898 | TOP OF PLANT ROOM | 8400

# IfcMember: ADSK_AU_Light Gauge-Zeds:Z20015 (11)
Type - PredefinedType: BRACE; Classification: B10 (Uniformat); Material: Metal - Steel - 345 MPa
Type - Pset_MemberCommon - IsExternal: no; LoadBearing: yes
Type - Pset_ProductRequirements - Category: Structural Framing
Pset_MemberCommon - Slope: 0 deg; Reference: Z20015
Pset_QuantityTakeOff - Reference: Z20015
Name (ADSK_AU_Light Gauge-Zeds:Z20015:...) | In | Span (mm)
564058 | Datum | 5645
564060 | Datum | 7360
980483 | Datum | 7500
980485 | Datum | 11100
980487 | Datum | 11100
980489 | Datum | 11100
980491 | TOP OF PLANT ROOM | 9240
980493 | TOP OF PLANT ROOM | 9240
980495 | TOP OF PLANT ROOM | 9240
980497 | TOP OF CEILING | 7300
980499 | TOP OF CEILING | 7600

# IfcMember: ADSK_AU_Round Bars (AS 3679_1):20ROD (4)
In: Datum
Type - PredefinedType: BRACE; Material: <Unnamed>
Type - Pset_MemberCommon - IsExternal: no; LoadBearing: yes
Type - Pset_ProductRequirements - Category: Structural Framing
Pset_MemberCommon - Reference: 20ROD
Pset_QuantityTakeOff - Reference: 20ROD
Name (ADSK_AU_Round Bars (AS 3679_1):20ROD:...) | Span (mm) | Slope (deg)
540915 | 5760 | 59.9919
837828 | 6680 | 45
852895 | 6680 | 45
939976 | 5902.1 | 58.7219

# IfcMember: ADSK_AU_UB-Universal Beams (AS 3679_1):410UB53.7, ADSK_AU_UB-Universal Beams (AS 3679_1):410UB53.7:611441
In: TOP OF CEILING
Type - PredefinedType: MEMBER; Material: Metal - Steel - 300 MPa
Type - Pset_MemberCommon - IsExternal: no; LoadBearing: yes
Type - Pset_ProductRequirements - Category: Structural Framing
Description: BP{65F570B7-3AC5-4045-A480-5CB0B2FCD890}
Pset_MemberCommon - Reference: 410UB53.7; Span: 29480.5 mm; Slope: 3.99999 deg
Pset_QuantityTakeOff - Reference: 410UB53.7
ProfileProperties - SectionFamily: {3C230476-3704-4959-9E77-0935CE245F3A}BP; Section: BP{65F570B7-3AC5-4045-A480-5CB0B2FCD890}

# IfcMember: ADSK_AU_UB-Universal Beams (AS 3679_1):460UB67.1, ADSK_AU_UB-Universal Beams (AS 3679_1):460UB67.1:454585
In: TOP OF CEILING
Type - PredefinedType: MEMBER; Material: Metal - Steel - 300 MPa
Type - Pset_MemberCommon - IsExternal: no; LoadBearing: yes
Type - Pset_ProductRequirements - Category: Structural Framing
Description: BP{9986EAF8-8209-4BFB-B9E4-6B7E1651E2E1}
Pset_MemberCommon - Reference: 460UB67.1; Span: 28728.9 mm; Slope: 4.00001 deg
Pset_QuantityTakeOff - Reference: 460UB67.1
ProfileProperties - SectionFamily: {3C230476-3704-4959-9E77-0935CE245F3A}BP; Section: BP{9986EAF8-8209-4BFB-B9E4-6B7E1651E2E1}

# IfcMember: ADSK_AU_UB-Universal Beams (AS 3679_1):530UB92.4 (3)
In: TOP OF CEILING
Type - PredefinedType: MEMBER; Material: Metal - Steel - 300 MPa
Type - Pset_MemberCommon - IsExternal: no; LoadBearing: yes
Type - Pset_ProductRequirements - Category: Structural Framing
Description: BP{3C230476-3704-4959-9E77-0935CE245F3A}
Pset_MemberCommon - Reference: 530UB92.4
Pset_QuantityTakeOff - Reference: 530UB92.4
ProfileProperties - SectionFamily: {3C230476-3704-4959-9E77-0935CE245F3A}BP; Section: BP{3C230476-3704-4959-9E77-0935CE245F3A}
Name (ADSK_AU_UB-Universal Beams (AS 3679_1):530UB92.4:...) | Span (mm) | Slope (deg)
447866 | 29307.5 | 3.99999
447601 | 29308.3 | 4
447848 | 29307.5 | 3.99999

# IfcOpeningElement: Opening (11)
Name | In
4 x Basic Wall:Cast In Situ - Concrete 200 RW2:426313 | Datum | Pset_ElementShading - Roughness: 304.8 mm; Pset_ManufacturerTypeInformation - Manufacturer: BW; Pset_OpeningElementCommon - Reference: Cast In Situ - Concrete 200 RW2; sets with these values: 2; Pset_ProductRequirements - Category: Lines: <Sketch>
Floor:FL-GHD-Cast In Situ - Concrete 120:1073663:2 | Datum | Pset_ElementShading - Roughness: 304.8 mm; Pset_OpeningElementCommon - Reference: FL-GHD-Cast In Situ - Concrete 120; sets with these values: 2; Pset_ProductRequirements - Category: Floors
6 x  | TOP OF CEILING

# IfcPlate (12)
Description: -; Material: Metal-Steel-Galvanised
Pset_PlateCommon - Reference: Not defined; IsExternal: no; LoadBearing: no
Name | In
10 x - | TOP OF CEILING
2 x - | Datum

# IfcSlab: FT-GHD-Pad:1500x1500x500 (2)
In: Datum
Type - PredefinedType: BASESLAB; Material: GHD-Concrete-Concrete_InSitu
Type - Pset_ManufacturerTypeInformation - Manufacturer: GHD
Type - Pset_ProductRequirements - Category: Structural Foundations
Type - Pset_ReinforcementBarPitchOfSlab - Description: PAD FOOTING
Type - Pset_SlabCommon - IsExternal: no
Classification: Pr_20_85_13_32 (Uniformat)
Pset_QuantityTakeOff - Reference: 1500x1500x500
Pset_ReinforcementBarPitchOfSlab - Reference: 1500x1500x500
Pset_SlabCommon - PitchAngle: 0 deg; Reference: 1500x1500x500
Name (FT-GHD-Pad:1500x1500x500:...)
1072004
1072356

# IfcSlab: FT-GHD-Pad:1500x2000x800 (2)
In: Datum
Type - PredefinedType: BASESLAB; Material: GHD-Concrete-Concrete_InSitu
Type - Pset_ManufacturerTypeInformation - Manufacturer: GHD
Type - Pset_ProductRequirements - Category: Structural Foundations
Type - Pset_ReinforcementBarPitchOfSlab - Description: PAD FOOTING
Type - Pset_SlabCommon - IsExternal: no
Classification: Pr_20_85_13_32 (Uniformat)
Pset_QuantityTakeOff - Reference: 1500x2000x800
Pset_ReinforcementBarPitchOfSlab - Reference: 1500x2000x800
Pset_SlabCommon - Reference: 1500x2000x800
Name (FT-GHD-Pad:1500x2000x800:...)
445333
445382 | Pset_SlabCommon - PitchAngle: 0 deg

# IfcSlab: FT-GHD-Pad:1500x800x950 2 (2)
In: Datum
Type - PredefinedType: BASESLAB; Material: GHD-Concrete-Concrete_InSitu
Type - Pset_ManufacturerTypeInformation - Manufacturer: GHD
Type - Pset_ProductRequirements - Category: Structural Foundations
Type - Pset_ReinforcementBarPitchOfSlab - Description: PAD FOOTING
Type - Pset_SlabCommon - IsExternal: no
Classification: Pr_20_85_13_32 (Uniformat)
Pset_QuantityTakeOff - Reference: 1500x800x950 2
Pset_ReinforcementBarPitchOfSlab - Reference: 1500x800x950 2
Pset_SlabCommon - PitchAngle: 0 deg; Reference: 1500x800x950 2
Name (FT-GHD-Pad:1500x800x950 2:...)
600472
604338

# IfcSlab: FT-GHD-Pad:1550x1800x1800 (4)
In: Datum
Type - PredefinedType: BASESLAB; Material: GHD-Concrete-Concrete_InSitu
Type - Pset_ManufacturerTypeInformation - Manufacturer: GHD
Type - Pset_ProductRequirements - Category: Structural Foundations
Type - Pset_ReinforcementBarPitchOfSlab - Description: PAD FOOTING
Type - Pset_SlabCommon - IsExternal: no
Classification: Pr_20_85_13_32 (Uniformat)
Pset_QuantityTakeOff - Reference: 1550x1800x1800
Pset_ReinforcementBarPitchOfSlab - Reference: 1550x1800x1800
Pset_SlabCommon - Reference: 1550x1800x1800
Name (FT-GHD-Pad:1550x1800x1800:...)
601594
605394
605727
605736

# IfcSlab: FT-GHD-Pad:1700x1000x1000 (2)
In: Datum
Type - PredefinedType: BASESLAB; Material: GHD-Concrete-Concrete_InSitu
Type - Pset_ManufacturerTypeInformation - Manufacturer: GHD
Type - Pset_ProductRequirements - Category: Structural Foundations
Type - Pset_ReinforcementBarPitchOfSlab - Description: PAD FOOTING
Type - Pset_SlabCommon - IsExternal: no
Classification: Pr_20_85_13_32 (Uniformat)
Pset_QuantityTakeOff - Reference: 1700x1000x1000
Pset_ReinforcementBarPitchOfSlab - Reference: 1700x1000x1000
Pset_SlabCommon - Reference: 1700x1000x1000
Name (FT-GHD-Pad:1700x1000x1000:...)
599181
605802

# IfcSlab: FT-GHD-Pad:1700x1700x800 (3)
In: Datum
Type - PredefinedType: BASESLAB; Material: GHD-Concrete-Concrete_InSitu
Type - Pset_ManufacturerTypeInformation - Manufacturer: GHD
Type - Pset_ProductRequirements - Category: Structural Foundations
Type - Pset_ReinforcementBarPitchOfSlab - Description: PAD FOOTING
Type - Pset_SlabCommon - IsExternal: no
Classification: Pr_20_85_13_32 (Uniformat)
Pset_QuantityTakeOff - Reference: 1700x1700x800
Pset_ReinforcementBarPitchOfSlab - Reference: 1700x1700x800
Pset_SlabCommon - Reference: 1700x1700x800
Name (FT-GHD-Pad:1700x1700x800:...)
445431
445676
445685

# IfcSlab: FT-GHD-Pad:1800x1800x800 (3)
In: Datum
Type - PredefinedType: BASESLAB; Material: GHD-Concrete-Concrete_InSitu
Type - Pset_ManufacturerTypeInformation - Manufacturer: GHD
Type - Pset_ProductRequirements - Category: Structural Foundations
Type - Pset_ReinforcementBarPitchOfSlab - Description: PAD FOOTING
Type - Pset_SlabCommon - IsExternal: no
Classification: Pr_20_85_13_32 (Uniformat)
Pset_QuantityTakeOff - Reference: 1800x1800x800
Pset_ReinforcementBarPitchOfSlab - Reference: 1800x1800x800
Pset_SlabCommon - PitchAngle: 0 deg; Reference: 1800x1800x800
Name (FT-GHD-Pad:1800x1800x800:...)
598261
598632
598755

# IfcSlab: FT-GHD-Pad:2000x1500x800, FT-GHD-Pad:2000x1500x800:1072738
In: Datum
Type - PredefinedType: BASESLAB; Material: GHD-Concrete-Concrete_InSitu
Type - Pset_ManufacturerTypeInformation - Manufacturer: GHD
Type - Pset_ProductRequirements - Category: Structural Foundations
Type - Pset_ReinforcementBarPitchOfSlab - Description: PAD FOOTING
Type - Pset_SlabCommon - IsExternal: no
Classification: Pr_20_85_13_32 (Uniformat)
Pset_QuantityTakeOff - Reference: 2000x1500x800
Pset_ReinforcementBarPitchOfSlab - Reference: 2000x1500x800
Pset_SlabCommon - Reference: 2000x1500x800

# IfcSlab: FT-GHD-Pad:2000x2000x600, FT-GHD-Pad:2000x2000x600:1071500
In: Datum
Type - PredefinedType: BASESLAB; Material: GHD-Concrete-Concrete_InSitu
Type - Pset_ManufacturerTypeInformation - Manufacturer: GHD
Type - Pset_ProductRequirements - Category: Structural Foundations
Type - Pset_ReinforcementBarPitchOfSlab - Description: PAD FOOTING
Type - Pset_SlabCommon - IsExternal: no
Classification: Pr_20_85_13_32 (Uniformat)
Pset_QuantityTakeOff - Reference: 2000x2000x600
Pset_ReinforcementBarPitchOfSlab - Reference: 2000x2000x600
Pset_SlabCommon - Reference: 2000x2000x600

# IfcSlab: FT-GHD-Pad:2000x3500x1000 (2)
In: Datum
Type - PredefinedType: BASESLAB; Material: GHD-Concrete-Concrete_InSitu
Type - Pset_ManufacturerTypeInformation - Manufacturer: GHD
Type - Pset_ProductRequirements - Category: Structural Foundations
Type - Pset_ReinforcementBarPitchOfSlab - Description: PAD FOOTING
Type - Pset_SlabCommon - IsExternal: no
Classification: Pr_20_85_13_32 (Uniformat)
Pset_QuantityTakeOff - Reference: 2000x3500x1000
Pset_ReinforcementBarPitchOfSlab - Reference: 2000x3500x1000
Pset_SlabCommon - Reference: 2000x3500x1000
Name (FT-GHD-Pad:2000x3500x1000:...)
601135
601540 | Pset_SlabCommon - PitchAngle: 0 deg

# IfcSlab: FT-GHD-Pad:2100x2100x800, FT-GHD-Pad:2100x2100x800:1072502
In: Datum
Type - PredefinedType: BASESLAB; Material: GHD-Concrete-Concrete_InSitu
Type - Pset_ManufacturerTypeInformation - Manufacturer: GHD
Type - Pset_ProductRequirements - Category: Structural Foundations
Type - Pset_ReinforcementBarPitchOfSlab - Description: PAD FOOTING
Type - Pset_SlabCommon - IsExternal: no
Classification: Pr_20_85_13_32 (Uniformat)
Pset_QuantityTakeOff - Reference: 2100x2100x800
Pset_ReinforcementBarPitchOfSlab - Reference: 2100x2100x800
Pset_SlabCommon - Reference: 2100x2100x800

# IfcSlab: FT-GHD-Pad:2500x2000x2000 (3)
In: Datum
Type - PredefinedType: BASESLAB; Material: GHD-Concrete-Concrete_InSitu
Type - Pset_ManufacturerTypeInformation - Manufacturer: GHD
Type - Pset_ProductRequirements - Category: Structural Foundations
Type - Pset_ReinforcementBarPitchOfSlab - Description: PAD FOOTING
Type - Pset_SlabCommon - IsExternal: no
Classification: Pr_20_85_13_32 (Uniformat)
Pset_QuantityTakeOff - Reference: 2500x2000x2000
Pset_ReinforcementBarPitchOfSlab - Reference: 2500x2000x2000
Pset_SlabCommon - Reference: 2500x2000x2000
Name (FT-GHD-Pad:2500x2000x2000:...)
598812
599149
599366

# IfcSlab: FT-GHD-Pad:750x4000x1800 (3)
In: Datum
Type - PredefinedType: BASESLAB; Material: GHD-Concrete-Concrete_InSitu
Type - Pset_ManufacturerTypeInformation - Manufacturer: GHD
Type - Pset_ProductRequirements - Category: Structural Foundations
Type - Pset_ReinforcementBarPitchOfSlab - Description: PAD FOOTING
Type - Pset_SlabCommon - IsExternal: no
Classification: Pr_20_85_13_32 (Uniformat)
Pset_QuantityTakeOff - Reference: 750x4000x1800
Pset_ReinforcementBarPitchOfSlab - Reference: 750x4000x1800
Pset_SlabCommon - Reference: 750x4000x1800
Name (FT-GHD-Pad:750x4000x1800:...) | PitchAngle (deg)
444830
445236 | 0
445245 | 0

# IfcSlab: FT-GHD-Pile-Round:450 BORED PILE (19)
In: Datum
Type - PredefinedType: BASESLAB; Material: Concrete_Cast in Situ
Type - Pset_ManufacturerTypeInformation - Manufacturer: GHD
Type - Pset_ProductRequirements - Category: Structural Foundations
Type - Pset_ReinforcementBarPitchOfSlab - Description: BORED PILE
Type - Pset_SlabCommon - IsExternal: no
Classification: Pr_20_85_62_18 (Uniformat)
Pset_QuantityTakeOff - Reference: 450 BORED PILE
Pset_ReinforcementBarPitchOfSlab - Reference: 450 BORED PILE
Pset_SlabCommon - Reference: 450 BORED PILE
Name (FT-GHD-Pile-Round:450 BORED PILE:...)
603741
603814
604048
604050
604288
604290
604402
604958
605318
632250
632287
876549
1033816
1033856
1033895
1120131
1120140 | Pset_SlabCommon - PitchAngle: 0 deg
1152920
1152929

# IfcSlab: Floor:Edge Strip 170 (3)
In: Datum
Type - PredefinedType: FLOOR; Material: GHD-Concrete-Concrete_InSitu 170 mm
Type - Pset_ElementShading - Roughness: 304.8 mm
Type - Pset_ProductRequirements - Category: Floors
Type - Pset_SlabCommon - IsExternal: no
Pset_QuantityTakeOff - Reference: Edge Strip 170; sets with these values: 2
Pset_SlabCommon - LoadBearing: yes; PitchAngle: 0 deg; Reference: Edge Strip 170
Name (Floor:Edge Strip 170:...)
462182
462278
1143135

# IfcSlab: Floor:Edge Strip 270, Floor:Edge Strip 270:461705
In: Datum
Type - PredefinedType: FLOOR; Material: GHD-Concrete-Concrete_InSitu 270 mm
Type - Pset_ElementShading - Roughness: 304.8 mm
Type - Pset_ProductRequirements - Category: Floors
Type - Pset_SlabCommon - IsExternal: no
Pset_QuantityTakeOff - Reference: Edge Strip 270; sets with these values: 2
Pset_SlabCommon - LoadBearing: yes; PitchAngle: 0 deg; Reference: Edge Strip 270

# IfcSlab: Floor:Edge Strip 370, Floor:Edge Strip 370:462354
In: Datum
Type - PredefinedType: FLOOR; Material: GHD-Concrete-Concrete_InSitu 370 mm
Type - Pset_ElementShading - Roughness: 304.8 mm
Type - Pset_ProductRequirements - Category: Floors
Type - Pset_SlabCommon - IsExternal: no
Pset_QuantityTakeOff - Reference: Edge Strip 370; sets with these values: 2
Pset_SlabCommon - LoadBearing: yes; PitchAngle: 0 deg; Reference: Edge Strip 370

# IfcSlab: Floor:FL-GHD-Cast In Situ - Concrete 120 (2)
In: Datum
Type - PredefinedType: FLOOR; Material: GHD-Concrete-Concrete_InSitu 120 mm
Type - Pset_ElementShading - Roughness: 304.8 mm
Type - Pset_ProductRequirements - Category: Floors
Type - Pset_SlabCommon - IsExternal: no
Pset_QuantityTakeOff - Reference: FL-GHD-Cast In Situ - Concrete 120; sets with these values: 2
Pset_SlabCommon - LoadBearing: yes; PitchAngle: 0 deg; Reference: FL-GHD-Cast In Situ - Concrete 120
Name (Floor:FL-GHD-Cast In Situ - Concrete 120:...)
1073663
1109386

# IfcSlab: Floor:FL-GHD-Cast In Situ - Concrete 150 (3)
In: Datum
Type - PredefinedType: FLOOR; Material: GHD-Concrete-Concrete_InSitu 150 mm
Type - Pset_ElementShading - Roughness: 304.8 mm
Type - Pset_ProductRequirements - Category: Floors
Type - Pset_SlabCommon - IsExternal: no
Pset_QuantityTakeOff - Reference: FL-GHD-Cast In Situ - Concrete 150; sets with these values: 2
Pset_SlabCommon - LoadBearing: yes; PitchAngle: 0 deg; Reference: FL-GHD-Cast In Situ - Concrete 150
Name (Floor:FL-GHD-Cast In Situ - Concrete 150:...)
1150521:3
1151186:3
1151993

# IfcSlab: Floor:FL-GHD-Cast In Situ - Concrete 150 (4)
In: Datum
Type - PredefinedType: FLOOR
Type - Pset_ElementShading - Roughness: 304.8 mm
Type - Pset_ProductRequirements - Category: Floors
Type - Pset_SlabCommon - IsExternal: no
Material: GHD-Concrete-Concrete_InSitu 150 mm
Pset_QuantityTakeOff - Reference: FL-GHD-Cast In Situ - Concrete 150; sets with these values: 2
Pset_SlabCommon - LoadBearing: yes; PitchAngle: 0 deg; Reference: FL-GHD-Cast In Situ - Concrete 150
Name (Floor:FL-GHD-Cast In Situ - Concrete 150:...)
1150521
1150521:2
1151186
1151186:2

# IfcSlab: Floor:FL-GHD-Cast In Situ - Concrete 170 (2)
In: Datum
Type - PredefinedType: FLOOR; Material: GHD-Concrete-Concrete_InSitu 170 mm
Type - Pset_ElementShading - Roughness: 304.8 mm
Type - Pset_ProductRequirements - Category: Floors
Type - Pset_SlabCommon - IsExternal: no
Pset_QuantityTakeOff - Reference: FL-GHD-Cast In Situ - Concrete 170; sets with these values: 2
Pset_SlabCommon - LoadBearing: yes; PitchAngle: 0 deg; Reference: FL-GHD-Cast In Situ - Concrete 170
Name (Floor:FL-GHD-Cast In Situ - Concrete 170:...)
660553
661332

# IfcSlab: Floor:FL-GHD-Cast In Situ - Concrete 200 (2)
In: Datum
Type - PredefinedType: FLOOR; Material: GHD-Concrete-Concrete_InSitu 200 mm
Type - Pset_ElementShading - Roughness: 304.8 mm
Type - Pset_ProductRequirements - Category: Floors
Type - Pset_SlabCommon - IsExternal: no
Pset_QuantityTakeOff - Reference: FL-GHD-Cast In Situ - Concrete 200; sets with these values: 2
Pset_SlabCommon - Reference: FL-GHD-Cast In Situ - Concrete 200; LoadBearing: yes; PitchAngle: 0 deg
Name (Floor:FL-GHD-Cast In Situ - Concrete 200:...)
444200
617485

# IfcSlab: Foundation Slab:PH-Foundation Slab (250), Foundation Slab:PH-Foundation Slab (250):627910
In: Datum
Type - PredefinedType: BASESLAB; Material: <Unnamed> 250 mm
Type - Pset_ElementShading - Roughness: 304.8 mm
Type - Pset_ProductRequirements - Category: Structural Foundations
Type - Pset_SlabCommon - IsExternal: no
Pset_QuantityTakeOff - Reference: PH-Foundation Slab (250); sets with these values: 2
Pset_SlabCommon - LoadBearing: yes; PitchAngle: 0 deg; Reference: PH-Foundation Slab (250)

# IfcSlab: Foundation Slab:PH-Foundation Slab (325) (2)
In: Datum
Type - PredefinedType: BASESLAB; Material: <Unnamed> 325 mm
Type - Pset_ElementShading - Roughness: 304.8 mm
Type - Pset_ProductRequirements - Category: Structural Foundations
Type - Pset_SlabCommon - IsExternal: no
Pset_QuantityTakeOff - Reference: PH-Foundation Slab (325); sets with these values: 2
Pset_SlabCommon - LoadBearing: yes; PitchAngle: 0 deg; Reference: PH-Foundation Slab (325)
Name (Foundation Slab:PH-Foundation Slab (325):...)
626956
1058275

# IfcSlab: Foundation Slab:PH-Foundation Slab (400), Foundation Slab:PH-Foundation Slab (400):1027104
In: Datum
Type - PredefinedType: BASESLAB; Material: <Unnamed> 400 mm
Type - Pset_ElementShading - Roughness: 304.8 mm
Type - Pset_ProductRequirements - Category: Structural Foundations
Type - Pset_SlabCommon - IsExternal: no
Pset_QuantityTakeOff - Reference: PH-Foundation Slab (400); sets with these values: 2
Pset_SlabCommon - LoadBearing: yes; PitchAngle: 0 deg; Reference: PH-Foundation Slab (400)

# IfcSlab: Foundation Slab:PH-Foundation Slab (600) (2)
In: Datum
Type - PredefinedType: BASESLAB; Material: <Unnamed> 600 mm
Type - Pset_ElementShading - Roughness: 304.8 mm
Type - Pset_ProductRequirements - Category: Structural Foundations
Type - Pset_SlabCommon - IsExternal: no
Pset_QuantityTakeOff - Reference: PH-Foundation Slab (600); sets with these values: 2
Pset_SlabCommon - LoadBearing: yes; PitchAngle: 0 deg; Reference: PH-Foundation Slab (600)
Name (Foundation Slab:PH-Foundation Slab (600):...)
627376
1058833

# IfcSlab: Foundation Slab:Strip Footing (450) (2)
In: Datum
Type - PredefinedType: BASESLAB; Material: <Unnamed> 450 mm
Type - Pset_ElementShading - Roughness: 304.8 mm
Type - Pset_ProductRequirements - Category: Structural Foundations
Type - Pset_SlabCommon - IsExternal: no
Pset_QuantityTakeOff - Reference: Strip Footing (450); sets with these values: 2
Pset_SlabCommon - LoadBearing: yes; PitchAngle: 0 deg; Reference: Strip Footing (450)
Name (Foundation Slab:Strip Footing (450):...)
631884
875787

# IfcWallStandardCase: Basic Wall:Cast In Situ - Concrete 200 RW2 (5)
In: Datum
Type - PredefinedType: STANDARD; Material: GHD-Concrete-Concrete_InSitu 200 mm
Type - Pset_ElementShading - Roughness: 304.8 mm
Type - Pset_ManufacturerTypeInformation - Manufacturer: BW
Type - Pset_ProductRequirements - Category: Walls
Type - Pset_ReinforcementBarPitchOfWall - Description: IN-SITU CONCRETE
Type - Pset_WallCommon - IsExternal: yes
Pset_QuantityTakeOff - Reference: Cast In Situ - Concrete 200 RW2
Pset_ReinforcementBarPitchOfWall - Reference: Cast In Situ - Concrete 200 RW2
Pset_WallCommon - LoadBearing: yes; ExtendToStructure: no; Reference: Cast In Situ - Concrete 200 RW2
Name (Basic Wall:Cast In Situ - Concrete 200 RW2:...)
607929
634240
638020
1034308
1140040

# IfcWallStandardCase: Basic Wall:Cast In Situ - Concrete 300 (7)
In: Datum
Type - PredefinedType: STANDARD; Material: GHD-Concrete-Concrete_InSitu 300 mm
Type - Pset_ElementShading - Roughness: 304.8 mm
Type - Pset_ManufacturerTypeInformation - Manufacturer: BW
Type - Pset_ProductRequirements - Category: Walls
Type - Pset_ReinforcementBarPitchOfWall - Description: IN-SITU CONCRETE
Type - Pset_WallCommon - IsExternal: yes
Pset_QuantityTakeOff - Reference: Cast In Situ - Concrete 300
Pset_ReinforcementBarPitchOfWall - Reference: Cast In Situ - Concrete 300
Pset_WallCommon - LoadBearing: yes; Reference: Cast In Situ - Concrete 300; ExtendToStructure: no
Name (Basic Wall:Cast In Situ - Concrete 300:...)
605974
606902
606978
607120
607266
607701
607912

# IfcWallStandardCase: Basic Wall:Cast In Situ - Concrete 300 RW3 (5)
In: Datum
Type - PredefinedType: STANDARD; Material: GHD-Concrete-Concrete_InSitu 300 mm
Type - Pset_ElementShading - Roughness: 304.8 mm
Type - Pset_ManufacturerTypeInformation - Manufacturer: BW
Type - Pset_ProductRequirements - Category: Walls
Type - Pset_ReinforcementBarPitchOfWall - Description: IN-SITU CONCRETE
Type - Pset_WallCommon - IsExternal: yes
Pset_QuantityTakeOff - Reference: Cast In Situ - Concrete 300 RW3
Pset_ReinforcementBarPitchOfWall - Reference: Cast In Situ - Concrete 300 RW3
Pset_WallCommon - LoadBearing: yes; ExtendToStructure: no; Reference: Cast In Situ - Concrete 300 RW3
Name (Basic Wall:Cast In Situ - Concrete 300 RW3:...)
608263
608280
1138697
1138872
1139000
